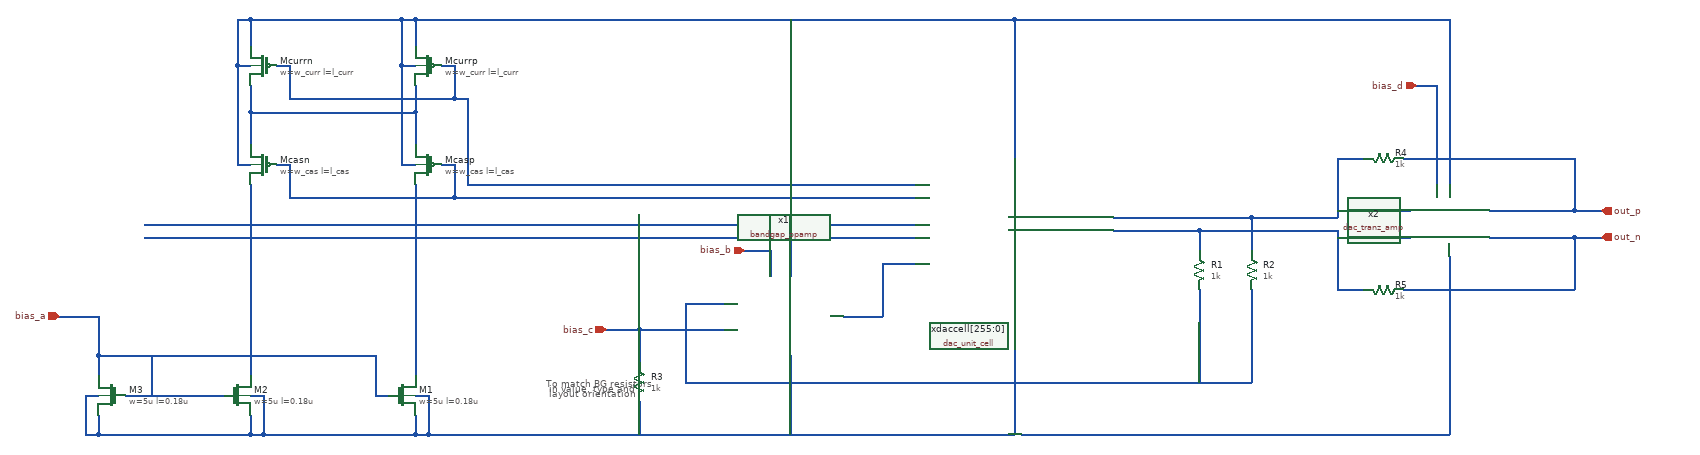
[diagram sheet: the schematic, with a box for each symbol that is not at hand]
v {xschem version=2.9.8 file_version=1.2}
G {}
K {}
V {}
S {}
E {}
T {To match BG resistors 
  in value, type and
  layout orientation} -100 150 0 0 0.2 0.2 {}
N -550 -250 -300 -250 {lab=#net1}
N -320 -320 -300 -320 {lab=#net2}
N -320 -390 -320 -320 {lab=#net2}
N -320 -390 -300 -390 {lab=#net2}
N -300 -390 -300 -350 {lab=#net2}
N -570 -320 -550 -320 {lab=#net2}
N -570 -390 -570 -320 {lab=#net2}
N -570 -390 -550 -390 {lab=#net2}
N -550 -390 -550 -350 {lab=#net2}
N -550 -390 -320 -390 {lab=#net2}
N -260 -320 -240 -320 {lab=#net3}
N -240 -320 -240 -270 {lab=#net3}
N -490 -270 -240 -270 {lab=#net3}
N -490 -320 -490 -270 {lab=#net3}
N -510 -320 -490 -320 {lab=#net3}
N -300 -250 -300 -200 {lab=#net1}
N -550 -250 -550 -200 {lab=#net1}
N -320 -170 -300 -170 {lab=#net2}
N -320 -320 -320 -170 {lab=#net2}
N -570 -320 -570 -170 {lab=#net2}
N -570 -170 -550 -170 {lab=#net2}
N -260 -170 -240 -170 {lab=#net4}
N -240 -170 -240 -120 {lab=#net4}
N -490 -120 -240 -120 {lab=#net4}
N -490 -170 -490 -120 {lab=#net4}
N -510 -170 -490 -170 {lab=#net4}
N -240 -120 460 -120 {lab=#net4}
N -220 -140 460 -140 {lab=#net3}
N -220 -270 -220 -140 {lab=#net3}
N -300 -290 -300 -250 {lab=#net1}
N -550 -290 -550 -250 {lab=#net1}
N -240 -270 -220 -270 {lab=#net3}
N 610 -380 610 -180 {lab=#net2}
N 610 -390 610 -380 {lab=#net2}
N -300 -390 610 -390 {lab=#net2}
N -710 -80 460 -80 {lab=#net5}
N -710 -60 460 -60 {lab=#net6}
N 890 -70 890 -40 {lab=#net7}
N 760 -70 890 -70 {lab=#net7}
N 970 -90 970 -40 {lab=#net8}
N 760 -90 970 -90 {lab=#net8}
N 350 60 410 60 {lab=#net9}
N 410 -20 410 60 {lab=#net9}
N 410 -20 460 -20 {lab=#net9}
N 110 40 170 40 {lab=#net10}
N 110 40 110 160 {lab=#net10}
N 110 160 970 160 {lab=#net10}
N 970 20 970 160 {lab=#net10}
N 890 20 890 160 {lab=#net10}
N -550 -140 -550 150 {lab=#net11}
N -300 -140 -300 150 {lab=#net12}
N -360 180 -340 180 {lab=bias_a}
N -360 120 -360 180 {lab=bias_a}
N -780 120 -360 120 {lab=bias_a}
N -780 120 -780 150 {lab=bias_a}
N -740 180 -590 180 {lab=bias_a}
N -700 120 -700 180 {lab=bias_a}
N -550 180 -530 180 {lab=#net13}
N -530 180 -530 240 {lab=#net13}
N -550 240 -530 240 {lab=#net13}
N -550 210 -550 240 {lab=#net13}
N -300 180 -280 180 {lab=#net13}
N -280 180 -280 240 {lab=#net13}
N -300 240 -280 240 {lab=#net13}
N -300 210 -300 240 {lab=#net13}
N -530 240 -300 240 {lab=#net13}
N -780 240 -550 240 {lab=#net13}
N -780 210 -780 240 {lab=#net13}
N -800 180 -780 180 {lab=#net13}
N -800 180 -800 240 {lab=#net13}
N -800 240 -780 240 {lab=#net13}
N -780 60 -780 120 {lab=bias_a}
N -840 60 -780 60 {lab=bias_a}
N 240 -40 240 0 {lab=bias_b}
N 200 -40 240 -40 {lab=bias_b}
N -280 240 610 240 {lab=#net13}
N 610 20 610 240 {lab=#net13}
N 40 80 40 130 {lab=bias_c}
N -10 80 40 80 {lab=bias_c}
N 40 190 40 240 {lab=#net13}
N 40 80 170 80 {lab=bias_c}
N 890 -70 1100 -70 {lab=#net7}
N 1100 -70 1100 20 {lab=#net7}
N 1100 20 1140 20 {lab=#net7}
N 970 -90 1100 -90 {lab=#net8}
N 1100 -180 1100 -90 {lab=#net8}
N 1100 -180 1140 -180 {lab=#net8}
N 1100 -100 1210 -100 {lab=#net8}
N 1100 -60 1210 -60 {lab=#net7}
N 1200 -180 1380 -180 {lab=out_p}
N 1460 -180 1460 -100 {lab=out_p}
N 1330 -100 1380 -100 {lab=out_p}
N 1330 -60 1380 -60 {lab=out_n}
N 1460 -60 1460 20 {lab=out_n}
N 1200 20 1380 20 {lab=out_n}
N 620 240 1270 240 {lab=#net14}
N 1270 -30 1270 240 {lab=#net14}
N 1250 -290 1250 -140 {lab=bias_d}
N 1220 -290 1250 -290 {lab=bias_d}
N 1270 -390 1270 -140 {lab=#net2}
N 610 -390 1270 -390 {lab=#net2}
N 1380 20 1460 20 {lab=out_n}
N 1380 -60 1460 -60 {lab=out_n}
N 1380 -100 1460 -100 {lab=out_p}
N 1380 -180 1460 -180 {lab=out_p}
N 1460 -100 1500 -100 {lab=out_p}
N 1460 -60 1500 -60 {lab=out_n}
N 270 120 270 240 { lab=#net13}
N 270 -390 270 -0 { lab=#net2}
C {dac_unit_cell/dac_unit_cell.sym} 610 -80 0 0 {name=xdaccell[255:0]}
C {pmos4.sym} -530 -320 0 1 {name=Mcurrn model=pmos w=w_curr l=l_curr m=m_curr}
C {pmos4.sym} -280 -320 0 1 {name=Mcurrp model=pmos w=w_curr l=l_curr m=m_curr}
C {pmos4.sym} -530 -170 0 1 {name=Mcasn model=pmos w=w_cas l=l_cas m=m_cas}
C {pmos4.sym} -280 -170 0 1 {name=Mcasp model=pmos w=w_cas l=l_cas m=m_cas}
C {dac_cmfb_opamp/bandgap_opamp.sym} 270 60 0 0 {name=x1}
C {res.sym} 890 -10 0 0 {name=R1
value=1k
footprint=1206
device=resistor
m=1}
C {res.sym} 970 -10 0 0 {name=R2
value=1k
footprint=1206
device=resistor
m=1}
C {nmos4.sym} -320 180 0 0 {name=M1 model=nmos w=5u l=0.18u m=1}
C {nmos4.sym} -570 180 0 0 {name=M2 model=nmos w=5u l=0.18u m=1}
C {nmos4.sym} -760 180 0 1 {name=M3 model=nmos w=5u l=0.18u m=1}
C {ipin.sym} -840 60 0 0 {name=p1 lab=bias_a}
C {ipin.sym} 200 -40 0 0 {name=p2 lab=bias_b}
C {ipin.sym} -10 80 0 0 {name=p3 lab=bias_c}
C {res.sym} 40 160 0 0 {name=R3
value=1k
footprint=1206
device=resistor
m=1}
C {res.sym} 1170 -180 1 0 {name=R4
value=1k
footprint=1206
device=resistor
m=1}
C {dac_transz_amp/dac_tranz_amp.sym} 1270 -80 0 0 {name=x2 w_in=20u w_cas=2u w_currp=2u w_currn=2u w_outn=2u w_currcas=2u w_casb=2u l_in=0.5u l_cas=0.5u l_currp=2u l_currn=2u l_outn=2u l_currcas=0.5u l_casb=0.5u m_currp=2 m_currp=2 m_currn=2 m_curro=2 m_outn=2 m_currcas=2 m_casb=2}
C {res.sym} 1170 20 1 0 {name=R5
value=1k
footprint=1206
device=resistor
m=1}
C {ipin.sym} 1220 -290 0 0 {name=p4 lab=bias_d}
C {opin.sym} 1500 -100 0 0 {name=p5 lab=out_p}
C {opin.sym} 1500 -60 0 0 {name=p6 lab=out_n}
